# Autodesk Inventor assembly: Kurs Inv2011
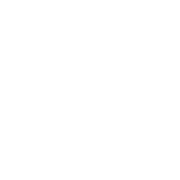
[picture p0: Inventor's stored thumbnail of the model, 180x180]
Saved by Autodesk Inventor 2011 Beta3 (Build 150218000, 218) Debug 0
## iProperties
Created: 2010-03
Part Number: Kurs Inv2011
Document SubType Name: Assembly
Designer: Johan Wedeen
Manufacturer: Standard
Standards Organization: Custom
Author: Johan Wedeen
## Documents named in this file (1)
- C:\Program Files\Autodesk\Inventor 2011\Templates\InventorKurs\Kurs Inv2011.iam
